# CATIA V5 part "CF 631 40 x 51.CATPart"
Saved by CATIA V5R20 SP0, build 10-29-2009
Part number: CF 631 40 x 51
Definition: NONE
Nomenclature: CF 631 40 x 51
Source: Unknown
Description: CF 631 40 x 51
Bounding box of the stored display mesh (mm): x -13 to 38, y -31.5 to 31.5, z -31.5 to 31.5
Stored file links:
  C:\Users\Utente\Desktop\IO LAVORO\3D X SITO CF\X SITO\CF 631\CF 631 40 x 51.CATPart

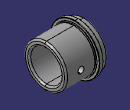
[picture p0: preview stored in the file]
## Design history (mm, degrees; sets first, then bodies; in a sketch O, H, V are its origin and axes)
Body1 "CF 631 40 x 51" (main body)
  Solid1: solid without history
